VERSION 5.7 ;
  NOWIREEXTENSIONATPIN ON ;
  DIVIDERCHAR "/" ;
  BUSBITCHARS "[]" ;
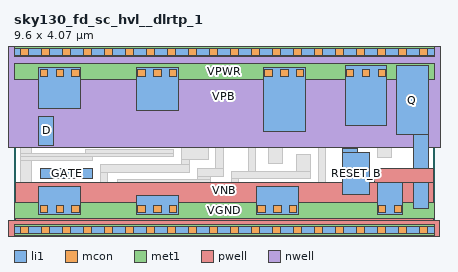
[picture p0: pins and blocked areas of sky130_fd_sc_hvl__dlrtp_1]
MACRO sky130_fd_sc_hvl__dlrtp_1
  CLASS BLOCK ;
  FOREIGN sky130_fd_sc_hvl__dlrtp_1 ;
  ORIGIN 0.000 0.000 ;
  SIZE 9.600 BY 4.070 ;
  PIN D
    ANTENNAGATEAREA 0.585000 ;
    PORT
      LAYER li1 ;
        RECT 0.570 1.930 0.900 2.600 ;
    END
  END D
  PIN GATE
    ANTENNAGATEAREA 0.585000 ;
    PORT
      LAYER li1 ;
        RECT 0.605 1.175 1.795 1.400 ;
    END
  END GATE
  PIN RESET_B
    ANTENNAGATEAREA 0.585000 ;
    PORT
      LAYER li1 ;
        RECT 7.515 1.780 7.845 1.855 ;
        RECT 7.515 0.810 8.120 1.780 ;
    END
  END RESET_B
  PIN VGND
    USE GROUND ;
    PORT
      LAYER li1 ;
        RECT 0.570 0.365 1.520 0.995 ;
        RECT 2.800 0.365 3.750 0.795 ;
        RECT 5.545 0.365 6.495 0.995 ;
        RECT 8.300 0.365 8.890 1.325 ;
      LAYER mcon ;
        RECT 0.600 0.395 0.770 0.565 ;
        RECT 0.960 0.395 1.130 0.565 ;
        RECT 1.320 0.395 1.490 0.565 ;
        RECT 2.830 0.395 3.000 0.565 ;
        RECT 3.190 0.395 3.360 0.565 ;
        RECT 3.550 0.395 3.720 0.565 ;
        RECT 5.575 0.395 5.745 0.565 ;
        RECT 5.935 0.395 6.105 0.565 ;
        RECT 6.295 0.395 6.465 0.565 ;
        RECT 8.330 0.395 8.500 0.565 ;
        RECT 8.690 0.395 8.860 0.565 ;
      LAYER met1 ;
        RECT 0.000 0.255 9.600 0.625 ;
    END
  END VGND
  PIN VNB
    ANTENNADIFFAREA 1.632000 ;
    PORT
      LAYER pwell ;
        RECT 8.250 1.085 9.580 1.415 ;
        RECT 0.030 0.215 9.580 1.085 ;
        RECT -0.130 -0.215 9.730 0.215 ;
      LAYER li1 ;
        RECT 0.000 -0.085 9.600 0.085 ;
      LAYER mcon ;
        RECT 0.155 -0.085 0.325 0.085 ;
        RECT 0.635 -0.085 0.805 0.085 ;
        RECT 1.115 -0.085 1.285 0.085 ;
        RECT 1.595 -0.085 1.765 0.085 ;
        RECT 2.075 -0.085 2.245 0.085 ;
        RECT 2.555 -0.085 2.725 0.085 ;
        RECT 3.035 -0.085 3.205 0.085 ;
        RECT 3.515 -0.085 3.685 0.085 ;
        RECT 3.995 -0.085 4.165 0.085 ;
        RECT 4.475 -0.085 4.645 0.085 ;
        RECT 4.955 -0.085 5.125 0.085 ;
        RECT 5.435 -0.085 5.605 0.085 ;
        RECT 5.915 -0.085 6.085 0.085 ;
        RECT 6.395 -0.085 6.565 0.085 ;
        RECT 6.875 -0.085 7.045 0.085 ;
        RECT 7.355 -0.085 7.525 0.085 ;
        RECT 7.835 -0.085 8.005 0.085 ;
        RECT 8.315 -0.085 8.485 0.085 ;
        RECT 8.795 -0.085 8.965 0.085 ;
        RECT 9.275 -0.085 9.445 0.085 ;
      LAYER met1 ;
        RECT 0.000 -0.115 9.600 0.115 ;
    END
  END VNB
  PIN VPB
    ANTENNADIFFAREA 1.632000 ;
    PORT
      LAYER nwell ;
        RECT -0.330 1.885 9.930 4.485 ;
      LAYER li1 ;
        RECT 0.000 3.985 9.600 4.155 ;
      LAYER mcon ;
        RECT 0.155 3.985 0.325 4.155 ;
        RECT 0.635 3.985 0.805 4.155 ;
        RECT 1.115 3.985 1.285 4.155 ;
        RECT 1.595 3.985 1.765 4.155 ;
        RECT 2.075 3.985 2.245 4.155 ;
        RECT 2.555 3.985 2.725 4.155 ;
        RECT 3.035 3.985 3.205 4.155 ;
        RECT 3.515 3.985 3.685 4.155 ;
        RECT 3.995 3.985 4.165 4.155 ;
        RECT 4.475 3.985 4.645 4.155 ;
        RECT 4.955 3.985 5.125 4.155 ;
        RECT 5.435 3.985 5.605 4.155 ;
        RECT 5.915 3.985 6.085 4.155 ;
        RECT 6.395 3.985 6.565 4.155 ;
        RECT 6.875 3.985 7.045 4.155 ;
        RECT 7.355 3.985 7.525 4.155 ;
        RECT 7.835 3.985 8.005 4.155 ;
        RECT 8.315 3.985 8.485 4.155 ;
        RECT 8.795 3.985 8.965 4.155 ;
        RECT 9.275 3.985 9.445 4.155 ;
      LAYER met1 ;
        RECT 0.000 3.955 9.600 4.185 ;
    END
  END VPB
  PIN VPWR
    USE POWER ;
    PORT
      LAYER li1 ;
        RECT 0.570 2.780 1.520 3.705 ;
        RECT 2.800 2.725 3.750 3.705 ;
        RECT 5.705 2.255 6.655 3.705 ;
        RECT 7.570 2.385 8.520 3.755 ;
      LAYER mcon ;
        RECT 0.600 3.505 0.770 3.675 ;
        RECT 0.960 3.505 1.130 3.675 ;
        RECT 1.320 3.505 1.490 3.675 ;
        RECT 2.830 3.505 3.000 3.675 ;
        RECT 3.190 3.505 3.360 3.675 ;
        RECT 3.550 3.505 3.720 3.675 ;
        RECT 5.735 3.505 5.905 3.675 ;
        RECT 6.095 3.505 6.265 3.675 ;
        RECT 6.455 3.505 6.625 3.675 ;
        RECT 7.600 3.505 7.770 3.675 ;
        RECT 7.960 3.505 8.130 3.675 ;
        RECT 8.320 3.505 8.490 3.675 ;
      LAYER met1 ;
        RECT 0.000 3.445 9.600 3.815 ;
    END
  END VPWR
  PIN Q
    ANTENNADIFFAREA 0.641250 ;
    PORT
      LAYER li1 ;
        RECT 8.735 2.175 9.475 3.755 ;
        RECT 9.140 0.495 9.475 2.175 ;
    END
  END Q
  OBS
      LAYER li1 ;
        RECT 0.140 1.750 0.390 3.610 ;
        RECT 1.700 2.195 2.030 3.610 ;
        RECT 2.290 2.545 2.620 3.245 ;
        RECT 4.560 2.895 4.890 3.245 ;
        RECT 4.560 2.725 5.525 2.895 ;
        RECT 2.290 2.375 4.785 2.545 ;
        RECT 4.615 2.295 4.785 2.375 ;
        RECT 1.700 2.025 4.435 2.195 ;
        RECT 1.625 1.750 3.655 1.845 ;
        RECT 0.140 1.675 3.655 1.750 ;
        RECT 0.140 1.580 1.795 1.675 ;
        RECT 3.835 1.605 4.435 2.025 ;
        RECT 4.615 1.965 5.175 2.295 ;
        RECT 0.140 0.495 0.390 1.580 ;
        RECT 3.835 1.495 4.005 1.605 ;
        RECT 1.975 1.325 4.005 1.495 ;
        RECT 4.615 1.395 4.785 1.965 ;
        RECT 1.975 0.995 2.145 1.325 ;
        RECT 4.185 1.225 4.785 1.395 ;
        RECT 5.355 1.345 5.525 2.725 ;
        RECT 6.960 2.205 7.390 3.005 ;
        RECT 6.960 2.075 8.470 2.205 ;
        RECT 5.810 2.035 8.470 2.075 ;
        RECT 5.810 1.905 7.130 2.035 ;
        RECT 5.810 1.525 6.140 1.905 ;
        RECT 6.450 1.345 6.780 1.725 ;
        RECT 4.185 1.145 4.495 1.225 ;
        RECT 1.700 0.495 2.145 0.995 ;
        RECT 2.370 0.975 4.495 1.145 ;
        RECT 4.965 1.175 6.780 1.345 ;
        RECT 4.965 0.995 5.135 1.175 ;
        RECT 6.960 0.995 7.130 1.905 ;
        RECT 8.300 1.995 8.470 2.035 ;
        RECT 8.300 1.665 8.630 1.995 ;
        RECT 2.370 0.495 2.620 0.975 ;
        RECT 4.675 0.495 5.135 0.995 ;
        RECT 6.755 0.495 7.130 0.995 ;
  END
END sky130_fd_sc_hvl__dlrtp_1
END LIBRARY

